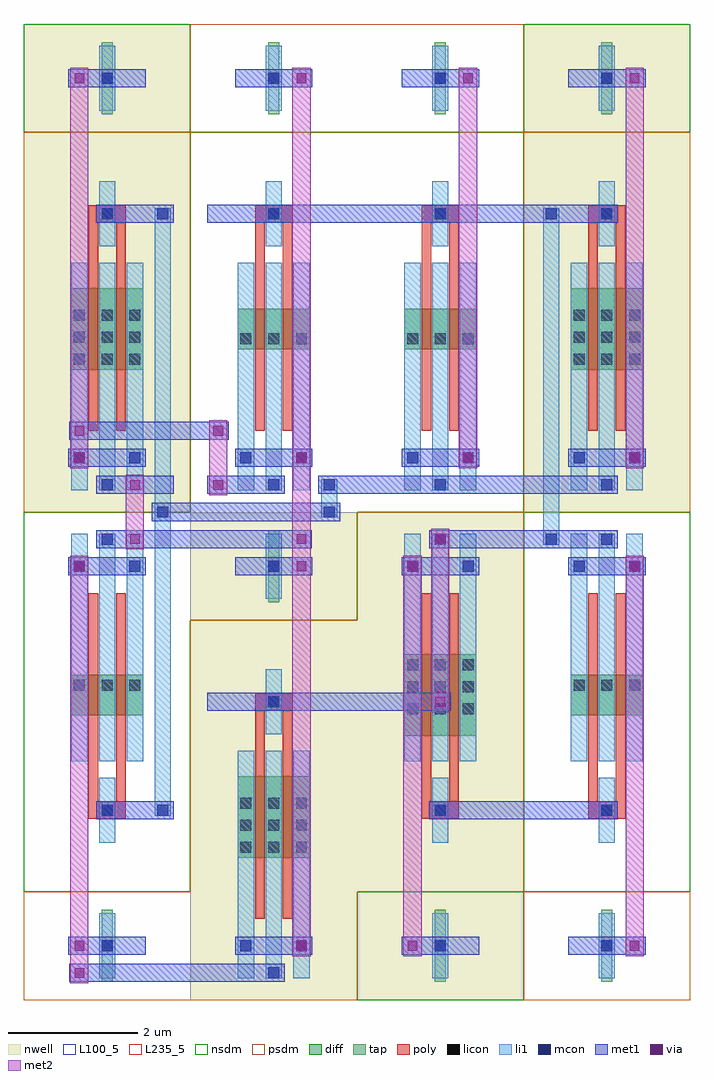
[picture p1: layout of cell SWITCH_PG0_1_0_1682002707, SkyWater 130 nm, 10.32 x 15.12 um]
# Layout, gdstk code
from math import pi, radians
import gdstk
lib = gdstk.Library(unit=1e-6, precision=1e-09)
def R(c, l, rs):  # rectangles x0, y0, x1, y1
    for r in rs: c.add(gdstk.rectangle(r[:2], r[2:], *l))
def A(c, l, x, y, w, h, nx, ny, dx, dy):  # array of equal rectangles
    R(c, l, [(x+i*dx, y+j*dy, x+i*dx+w, y+j*dy+h) for i in range(nx) for j in range(ny)])
def P(c, l, *ps):  # polygons
    for p in ps: c.add(gdstk.Polygon(p, *l))
nwell = (64, 20)
diff = (65, 20)
tap = (65, 44)
poly = (66, 20)
licon = (66, 44)
li1 = (67, 20)
mcon = (67, 44)
met1 = (68, 20)
via = (68, 44)
met2 = (69, 20)
nsdm = (93, 44)
psdm = (94, 20)
L100_5 = (100, 5)
L235_5 = (235, 5)

nmos_s_18927041_x1_y1_16 = lib.new_cell('NMOS_S_18927041_X1_Y1_1682002703_1682002704_1682002707')
R(nmos_s_18927041_x1_y1_16, diff, [(0.735,2.52,1.845,3.15)])
R(nmos_s_18927041_x1_y1_16, tap, [(1.205,6.16,1.375,7.28)])
R(nmos_s_18927041_x1_y1_16, poly, [(1,1.26,1.15,4.62), (1.43,1.26,1.58,4.62), (1,4.485,1.58,4.755)])
A(nmos_s_18927041_x1_y1_16, licon, 0.775, 2.6, 0.17, 0.17, 3, 1, 0.43, 0)
R(nmos_s_18927041_x1_y1_16, licon, [(1.205,4.535,1.375,4.705), (1.205,6.635,1.375,6.805)])
A(nmos_s_18927041_x1_y1_16, li1, 0.735, 0.335, 0.25, 3.53, 3, 1, 0.43, 0)
R(nmos_s_18927041_x1_y1_16, li1, [(1.165,4.115,1.415,5.125), (1.165,6.215,1.415,7.225)])
R(nmos_s_18927041_x1_y1_16, mcon, [(1.205,0.335,1.375,0.505), (0.775,0.755,0.945,0.925), (1.635,0.755,1.805,0.925), (1.205,4.535,1.375,4.705), (1.205,6.635,1.375,6.805)])
R(nmos_s_18927041_x1_y1_16, met1, [(0.26,0.28,1.46,0.56), (0.69,0.7,1.89,0.98), (0.26,4.48,1.46,4.76), (0.69,6.58,1.89,6.86)])
R(nmos_s_18927041_x1_y1_16, via, [(1.645,0.765,1.795,0.915), (1.645,6.645,1.795,6.795)])
R(nmos_s_18927041_x1_y1_16, met2, [(1.58,0.68,1.86,6.88)])
R(nmos_s_18927041_x1_y1_16, nsdm, [(0,0,2.58,5.88)])
R(nmos_s_18927041_x1_y1_16, psdm, [(0,5.88,2.58,7.56)])
R(nmos_s_18927041_x1_y1_16, L100_5, [(0,0,2.58,7.56)])

pmos_s_92403763_x1_y1_16 = lib.new_cell('PMOS_S_92403763_X1_Y1_1682002704_1682002704_1682002707')
R(pmos_s_92403763_x1_y1_16, nwell, [(0,0,2.58,7.56)])
R(pmos_s_92403763_x1_y1_16, diff, [(0.735,2.205,1.845,3.465)])
R(pmos_s_92403763_x1_y1_16, tap, [(1.205,6.16,1.375,7.28)])
R(pmos_s_92403763_x1_y1_16, poly, [(1,1.26,1.15,4.62), (1.43,1.26,1.58,4.62), (1,4.485,1.58,4.755)])
A(pmos_s_92403763_x1_y1_16, licon, 0.775, 2.285, 0.17, 0.17, 3, 3, 0.43, 0.34)
R(pmos_s_92403763_x1_y1_16, licon, [(1.205,4.535,1.375,4.705), (1.205,6.635,1.375,6.805)])
A(pmos_s_92403763_x1_y1_16, li1, 0.735, 0.335, 0.25, 3.53, 3, 1, 0.43, 0)
R(pmos_s_92403763_x1_y1_16, li1, [(1.165,4.115,1.415,5.125), (1.165,6.215,1.415,7.225)])
R(pmos_s_92403763_x1_y1_16, mcon, [(1.205,0.335,1.375,0.505), (0.775,0.755,0.945,0.925), (1.635,0.755,1.805,0.925), (1.205,4.535,1.375,4.705), (1.205,6.635,1.375,6.805)])
R(pmos_s_92403763_x1_y1_16, met1, [(0.26,0.28,1.46,0.56), (0.69,0.7,1.89,0.98), (0.26,4.48,1.46,4.76), (0.69,6.58,1.89,6.86)])
R(pmos_s_92403763_x1_y1_16, via, [(1.645,0.765,1.795,0.915), (1.645,6.645,1.795,6.795)])
R(pmos_s_92403763_x1_y1_16, met2, [(1.58,0.68,1.86,6.88)])
R(pmos_s_92403763_x1_y1_16, nsdm, [(0,5.88,2.58,7.56)])
R(pmos_s_92403763_x1_y1_16, psdm, [(0,0,2.58,5.88)])
R(pmos_s_92403763_x1_y1_16, L100_5, [(0,0,2.58,7.56)])

inv_26057185_1_0_1682002 = lib.new_cell('INV_26057185_1_0_1682002704_1682002707')
R(inv_26057185_1_0_1682002, li1, [(2.025,2.855,2.275,3.025), (2.025,2.855,2.275,3.025), (2.025,2.94,2.275,12.18), (2.025,12.095,2.275,12.265), (2.025,12.095,2.275,12.265)])
R(inv_26057185_1_0_1682002, mcon, [(2.065,2.855,2.235,3.025), (2.065,2.855,2.235,3.025), (2.065,12.095,2.235,12.265), (2.065,12.095,2.235,12.265)])
R(inv_26057185_1_0_1682002, met1, [(1.98,2.8,2.32,3.08), (1.98,2.8,2.32,3.08), (1.56,7,1.88,7.28), (1.56,7,1.88,7.28), (1.56,7.84,1.88,8.12), (1.56,7.84,1.88,8.12), (1.98,12.04,2.32,12.32), (1.98,12.04,2.32,12.32)])
P(inv_26057185_1_0_1682002, met1, [(0,0),(0,0),(0,0),(0,0)],
  [(0,0),(0,0),(0,0),(0,0)],
  [(0,0),(0,0),(0,0),(0,0)],
  [(0,0),(0,0),(0,0),(0,0)])
R(inv_26057185_1_0_1682002, via, [(1.645,7.065,1.795,7.215), (1.645,7.065,1.795,7.215), (1.645,7.905,1.795,8.055), (1.645,7.905,1.795,8.055)])
R(inv_26057185_1_0_1682002, met2, [(1.58,6.98,1.86,7.3), (1.58,6.98,1.86,7.3), (1.58,7.14,1.86,7.98), (1.58,7.82,1.86,8.14), (1.58,7.82,1.86,8.14)])
P(inv_26057185_1_0_1682002, met2, [(0,0),(0,0),(0,0),(0,0)],
  [(0,0),(0,0),(0,0),(0,0)])
R(inv_26057185_1_0_1682002, L235_5, [(0,0,2.58,15.12)])
inv_26057185_1_0_1682002.add(gdstk.Reference(nmos_s_18927041_x1_y1_16, (2.58,7.56), rotation=pi))
inv_26057185_1_0_1682002.add(gdstk.Reference(pmos_s_92403763_x1_y1_16, (2.58,7.56), rotation=pi, x_reflection=True))

c_nmos_s_18927041_x1_y1_16 = lib.new_cell('NMOS_S_18927041_X1_Y1_1682002705_1682002707')
R(c_nmos_s_18927041_x1_y1_16, diff, [(0.735,2.52,1.845,3.15)])
R(c_nmos_s_18927041_x1_y1_16, tap, [(1.205,6.16,1.375,7.28)])
R(c_nmos_s_18927041_x1_y1_16, poly, [(1,1.26,1.15,4.62), (1.43,1.26,1.58,4.62), (1,4.485,1.58,4.755)])
A(c_nmos_s_18927041_x1_y1_16, licon, 0.775, 2.6, 0.17, 0.17, 3, 1, 0.43, 0)
R(c_nmos_s_18927041_x1_y1_16, licon, [(1.205,4.535,1.375,4.705), (1.205,6.635,1.375,6.805)])
A(c_nmos_s_18927041_x1_y1_16, li1, 0.735, 0.335, 0.25, 3.53, 3, 1, 0.43, 0)
R(c_nmos_s_18927041_x1_y1_16, li1, [(1.165,4.115,1.415,5.125), (1.165,6.215,1.415,7.225)])
R(c_nmos_s_18927041_x1_y1_16, mcon, [(1.205,0.335,1.375,0.505), (0.775,0.755,0.945,0.925), (1.635,0.755,1.805,0.925), (1.205,4.535,1.375,4.705), (1.205,6.635,1.375,6.805)])
R(c_nmos_s_18927041_x1_y1_16, met1, [(0.26,0.28,1.46,0.56), (0.69,0.7,1.89,0.98), (0.26,4.48,1.46,4.76), (0.69,6.58,1.89,6.86)])
R(c_nmos_s_18927041_x1_y1_16, via, [(1.645,0.765,1.795,0.915), (1.645,6.645,1.795,6.795)])
R(c_nmos_s_18927041_x1_y1_16, met2, [(1.58,0.68,1.86,6.88)])
R(c_nmos_s_18927041_x1_y1_16, nsdm, [(0,0,2.58,5.88)])
R(c_nmos_s_18927041_x1_y1_16, psdm, [(0,5.88,2.58,7.56)])
R(c_nmos_s_18927041_x1_y1_16, L100_5, [(0,0,2.58,7.56)])

c_pmos_s_92403763_x1_y1_16 = lib.new_cell('PMOS_S_92403763_X1_Y1_1682002706_1682002707')
R(c_pmos_s_92403763_x1_y1_16, nwell, [(0,0,2.58,7.56)])
R(c_pmos_s_92403763_x1_y1_16, diff, [(0.735,2.205,1.845,3.465)])
R(c_pmos_s_92403763_x1_y1_16, tap, [(1.205,6.16,1.375,7.28)])
R(c_pmos_s_92403763_x1_y1_16, poly, [(1,1.26,1.15,4.62), (1.43,1.26,1.58,4.62), (1,4.485,1.58,4.755)])
A(c_pmos_s_92403763_x1_y1_16, licon, 0.775, 2.285, 0.17, 0.17, 3, 3, 0.43, 0.34)
R(c_pmos_s_92403763_x1_y1_16, licon, [(1.205,4.535,1.375,4.705), (1.205,6.635,1.375,6.805)])
A(c_pmos_s_92403763_x1_y1_16, li1, 0.735, 0.335, 0.25, 3.53, 3, 1, 0.43, 0)
R(c_pmos_s_92403763_x1_y1_16, li1, [(1.165,4.115,1.415,5.125), (1.165,6.215,1.415,7.225)])
R(c_pmos_s_92403763_x1_y1_16, mcon, [(1.205,0.335,1.375,0.505), (0.775,0.755,0.945,0.925), (1.635,0.755,1.805,0.925), (1.205,4.535,1.375,4.705), (1.205,6.635,1.375,6.805)])
R(c_pmos_s_92403763_x1_y1_16, met1, [(0.26,0.28,1.46,0.56), (0.69,0.7,1.89,0.98), (0.26,4.48,1.46,4.76), (0.69,6.58,1.89,6.86)])
R(c_pmos_s_92403763_x1_y1_16, via, [(1.645,0.765,1.795,0.915), (1.645,6.645,1.795,6.795)])
R(c_pmos_s_92403763_x1_y1_16, met2, [(1.58,0.68,1.86,6.88)])
R(c_pmos_s_92403763_x1_y1_16, nsdm, [(0,5.88,2.58,7.56)])
R(c_pmos_s_92403763_x1_y1_16, psdm, [(0,0,2.58,5.88)])
R(c_pmos_s_92403763_x1_y1_16, L100_5, [(0,0,2.58,7.56)])

switch_pg0_1_0_168200270 = lib.new_cell('SWITCH_PG0_1_0_1682002707')
R(switch_pg0_1_0_168200270, li1, [(8.045,7.055,8.295,7.225), (8.045,7.055,8.295,7.225), (8.045,7.055,8.295,7.225), (8.045,7.055,8.295,7.225), (8.045,7.055,8.295,7.225), (8.045,7.055,8.295,7.225), (8.045,7.14,8.295,12.18), (2.025,7.475,2.275,7.645), (2.025,7.475,2.275,7.645), (2.025,7.475,2.275,7.645), (2.025,7.475,2.275,7.645), (4.605,7.475,4.855,7.645), (4.605,7.475,4.855,7.645), (4.605,7.475,4.855,7.645), (4.605,7.475,4.855,7.645), (4.605,7.56,4.855,7.98), (4.605,7.895,4.855,8.065), (4.605,7.895,4.855,8.065), (4.605,7.895,4.855,8.065), (4.605,7.895,4.855,8.065), (8.045,12.095,8.295,12.265), (8.045,12.095,8.295,12.265), (8.045,12.095,8.295,12.265), (8.045,12.095,8.295,12.265), (8.045,12.095,8.295,12.265), (8.045,12.095,8.295,12.265)])
P(switch_pg0_1_0_168200270, li1, [(0,0),(0,0),(0,0),(0,0)])
R(switch_pg0_1_0_168200270, mcon, [(8.085,7.055,8.255,7.225), (8.085,7.055,8.255,7.225), (8.085,7.055,8.255,7.225), (8.085,7.055,8.255,7.225), (8.085,7.055,8.255,7.225), (8.085,7.055,8.255,7.225), (2.065,7.475,2.235,7.645), (2.065,7.475,2.235,7.645), (2.065,7.475,2.235,7.645), (2.065,7.475,2.235,7.645), (4.645,7.475,4.815,7.645), (4.645,7.475,4.815,7.645), (4.645,7.475,4.815,7.645), (4.645,7.475,4.815,7.645), (4.645,7.895,4.815,8.065), (4.645,7.895,4.815,8.065), (4.645,7.895,4.815,8.065), (4.645,7.895,4.815,8.065), (8.085,12.095,8.255,12.265), (8.085,12.095,8.255,12.265), (8.085,12.095,8.255,12.265), (8.085,12.095,8.255,12.265), (8.085,12.095,8.255,12.265), (8.085,12.095,8.255,12.265)])
R(switch_pg0_1_0_168200270, met1, [(0.7,0.28,1.02,0.56), (0.7,0.28,1.02,0.56), (0.86,0.28,3.01,0.56), (7.31,2.8,8.17,3.08), (3.87,4.48,6.45,4.76), (6.29,4.48,6.61,4.76), (6.29,4.48,6.61,4.76), (6.29,4.48,6.61,4.76), (6.29,4.48,6.61,4.76), (6.29,4.48,6.61,4.76), (6.29,4.48,6.61,4.76), (6.29,4.48,6.61,4.76), (6.29,4.48,6.61,4.76), (6.29,4.48,6.61,4.76), (6.29,4.48,6.61,4.76), (2.15,7,4.3,7.28), (4.14,7,4.46,7.28), (4.14,7,4.46,7.28), (4.14,7,4.46,7.28), (4.14,7,4.46,7.28), (6.29,7,6.61,7.28), (6.29,7,6.61,7.28), (6.29,7,6.61,7.28), (6.29,7,6.61,7.28), (6.29,7,6.61,7.28), (6.29,7,6.61,7.28), (6.29,7,6.61,7.28), (6.29,7,6.61,7.28), (6.29,7,6.61,7.28), (6.29,7,6.61,7.28), (7.31,7,8.17,7.28), (8,7,8.34,7.28), (8,7,8.34,7.28), (8,7,8.34,7.28), (8,7,8.34,7.28), (8,7,8.34,7.28), (8,7,8.34,7.28), (1.98,7.42,2.32,7.7), (1.98,7.42,2.32,7.7), (1.98,7.42,2.32,7.7), (1.98,7.42,2.32,7.7), (2.15,7.42,4.73,7.7), (4.56,7.42,4.9,7.7), (4.56,7.42,4.9,7.7), (4.56,7.42,4.9,7.7), (4.56,7.42,4.9,7.7), (2.85,7.84,3.17,8.12), (2.85,7.84,3.17,8.12), (4.56,7.84,4.9,8.12), (4.56,7.84,4.9,8.12), (4.56,7.84,4.9,8.12), (4.56,7.84,4.9,8.12), (4.73,7.84,5.59,8.12), (6.45,7.84,8.17,8.12), (0.7,8.68,1.02,8.96), (0.7,8.68,1.02,8.96), (0.86,8.68,3.01,8.96), (2.85,8.68,3.17,8.96), (2.85,8.68,3.17,8.96), (3.87,12.04,5.59,12.32), (6.45,12.04,8.17,12.32), (8,12.04,8.34,12.32), (8,12.04,8.34,12.32), (8,12.04,8.34,12.32), (8,12.04,8.34,12.32), (8,12.04,8.34,12.32), (8,12.04,8.34,12.32)])
P(switch_pg0_1_0_168200270, met1, [(0,0),(0,0),(0,0),(0,0)],
  [(0,0),(0,0),(0,0),(0,0)],
  [(0,0),(0,0),(0,0),(0,0)],
  [(0,0),(0,0),(0,0),(0,0)],
  [(0,0),(0,0),(0,0),(0,0)],
  [(0,0),(0,0),(0,0),(0,0)],
  [(0,0),(0,0),(0,0),(0,0)],
  [(0,0),(0,0),(0,0),(0,0)],
  [(0,0),(0,0),(0,0),(0,0)],
  [(0,0),(0,0),(0,0),(0,0)],
  [(0,0),(0,0),(0,0),(0,0)],
  [(0,0),(0,0),(0,0),(0,0)],
  [(0,0),(0,0),(0,0),(0,0)],
  [(0,0),(0,0),(0,0),(0,0)],
  [(0,0),(0,0),(0,0),(0,0)],
  [(0,0),(0,0),(0,0),(0,0)],
  [(0,0),(0,0),(0,0),(0,0)],
  [(0,0),(0,0),(0,0),(0,0)],
  [(0,0),(0,0),(0,0),(0,0)],
  [(0,0),(0,0),(0,0),(0,0)])
R(switch_pg0_1_0_168200270, via, [(0.785,0.345,0.935,0.495), (0.785,0.345,0.935,0.495), (6.375,4.545,6.525,4.695), (6.375,4.545,6.525,4.695), (6.375,4.545,6.525,4.695), (6.375,4.545,6.525,4.695), (6.375,4.545,6.525,4.695), (6.375,4.545,6.525,4.695), (6.375,4.545,6.525,4.695), (6.375,4.545,6.525,4.695), (6.375,4.545,6.525,4.695), (6.375,4.545,6.525,4.695), (4.225,7.065,4.375,7.215), (4.225,7.065,4.375,7.215), (4.225,7.065,4.375,7.215), (4.225,7.065,4.375,7.215), (6.375,7.065,6.525,7.215), (6.375,7.065,6.525,7.215), (6.375,7.065,6.525,7.215), (6.375,7.065,6.525,7.215), (6.375,7.065,6.525,7.215), (6.375,7.065,6.525,7.215), (6.375,7.065,6.525,7.215), (6.375,7.065,6.525,7.215), (6.375,7.065,6.525,7.215), (6.375,7.065,6.525,7.215), (2.935,7.905,3.085,8.055), (2.935,7.905,3.085,8.055), (0.785,8.745,0.935,8.895), (0.785,8.745,0.935,8.895), (2.935,8.745,3.085,8.895), (2.935,8.745,3.085,8.895)])
R(switch_pg0_1_0_168200270, met2, [(0.72,0.26,1,0.58), (0.72,0.26,1,0.58), (0.72,0.42,1,0.84), (6.31,4.46,6.59,4.78), (6.31,4.46,6.59,4.78), (6.31,4.46,6.59,4.78), (6.31,4.46,6.59,4.78), (6.31,4.46,6.59,4.78), (6.31,4.46,6.59,4.78), (6.31,4.46,6.59,4.78), (6.31,4.46,6.59,4.78), (6.31,4.46,6.59,4.78), (6.31,4.46,6.59,4.78), (6.31,4.62,6.59,7.14), (4.16,6.72,4.44,7.14), (4.16,6.98,4.44,7.3), (4.16,6.98,4.44,7.3), (4.16,6.98,4.44,7.3), (4.16,6.98,4.44,7.3), (6.31,6.98,6.59,7.3), (6.31,6.98,6.59,7.3), (6.31,6.98,6.59,7.3), (6.31,6.98,6.59,7.3), (6.31,6.98,6.59,7.3), (6.31,6.98,6.59,7.3), (6.31,6.98,6.59,7.3), (6.31,6.98,6.59,7.3), (6.31,6.98,6.59,7.3), (6.31,6.98,6.59,7.3), (4.16,7.14,4.44,8.4), (2.87,7.82,3.15,8.14), (2.87,7.82,3.15,8.14), (2.87,7.98,3.15,8.82), (0.72,8.66,1,8.98), (0.72,8.66,1,8.98), (2.87,8.66,3.15,8.98), (2.87,8.66,3.15,8.98)])
P(switch_pg0_1_0_168200270, met2, [(0,0),(0,0),(0,0),(0,0)],
  [(0,0),(0,0),(0,0),(0,0)],
  [(0,0),(0,0),(0,0),(0,0)],
  [(0,0),(0,0),(0,0),(0,0)],
  [(0,0),(0,0),(0,0),(0,0)],
  [(0,0),(0,0),(0,0),(0,0)],
  [(0,0),(0,0),(0,0),(0,0)],
  [(0,0),(0,0),(0,0),(0,0)],
  [(0,0),(0,0),(0,0),(0,0)])
R(switch_pg0_1_0_168200270, L235_5, [(0,0,10.32,15.12)])
switch_pg0_1_0_168200270.add(gdstk.Reference(inv_26057185_1_0_1682002, (0,0)))
switch_pg0_1_0_168200270.add(gdstk.Reference(c_nmos_s_18927041_x1_y1_16, (7.74,7.56), x_reflection=True))
switch_pg0_1_0_168200270.add(gdstk.Reference(c_nmos_s_18927041_x1_y1_16, (5.16,7.56)))
switch_pg0_1_0_168200270.add(gdstk.Reference(c_nmos_s_18927041_x1_y1_16, (2.58,7.56)))
switch_pg0_1_0_168200270.add(gdstk.Reference(c_pmos_s_92403763_x1_y1_16, (7.74,7.56), rotation=pi))
switch_pg0_1_0_168200270.add(gdstk.Reference(c_pmos_s_92403763_x1_y1_16, (7.74,7.56)))
switch_pg0_1_0_168200270.add(gdstk.Reference(c_pmos_s_92403763_x1_y1_16, (2.58,0)))

lib.write_gds('SWITCH_PG0_1_0_1682002707.gds')
